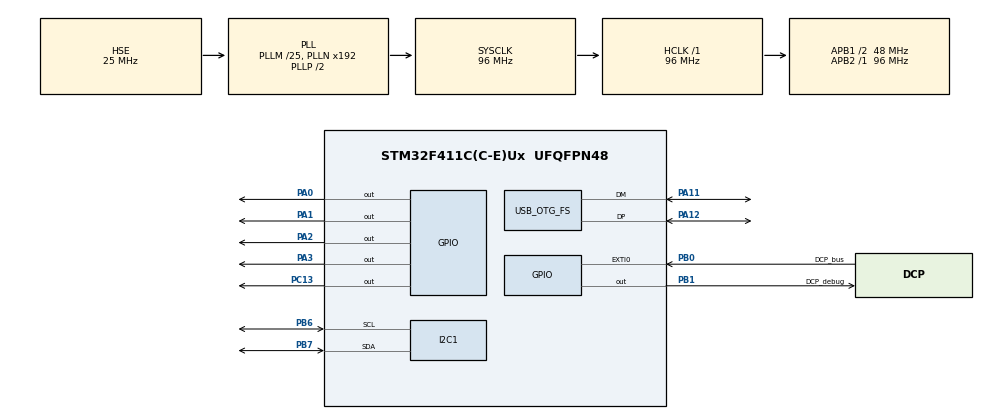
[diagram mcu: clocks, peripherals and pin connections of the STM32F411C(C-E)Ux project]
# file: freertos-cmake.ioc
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FREERTOS.Tasks01=defaultTask,0,128,StartDefaultTask,Default,NULL,Dynamic,NULL,NULL
FREERTOS.configUSE_NEWLIB_REENTRANT=1
Mcu.Family=STM32F4
Mcu.Name=STM32F411C(C-E)Ux
Mcu.Package=UFQFPN48
NVIC.EXTI0_IRQn=true\:5\:0\:false\:false\:true\:true\:true\:true\:true
NVIC.OTG_FS_IRQn=true\:5\:0\:false\:false\:true\:true\:false\:true\:true
NVIC.PriorityGroup=NVIC_PRIORITYGROUP_4
NVIC.TIM1_UP_TIM10_IRQn=true\:15\:0\:false\:false\:true\:false\:false\:true\:true
NVIC.TimeBase=TIM1_UP_TIM10_IRQn
NVIC.TimeBaseIP=TIM1
PA0-WKUP.Signal=GPIO_Output
PA1.Signal=GPIO_Output
PA11.Mode=Device_Only
PA11.Signal=USB_OTG_FS_DM
PA12.Mode=Device_Only
PA12.Signal=USB_OTG_FS_DP
PA2.Signal=GPIO_Output
PA3.Signal=GPIO_Output
PB0.GPIO_Label=DCP_bus
PB0.GPIO_ModeDefaultEXTI=GPIO_MODE_IT_FALLING
PB0.Signal=GPXTI0
PB1.GPIO_Label=DCP_debug
PB1.Signal=GPIO_Output
PB6.Mode=I2C
PB6.Signal=I2C1_SCL
PB7.Mode=I2C
PB7.Signal=I2C1_SDA
PC13-ANTI_TAMP.Signal=GPIO_Output
PC14-OSC32_IN.Mode=LSE-External-Oscillator
PC14-OSC32_IN.Signal=RCC_OSC32_IN
PC15-OSC32_OUT.Mode=LSE-External-Oscillator
PC15-OSC32_OUT.Signal=RCC_OSC32_OUT
PH0\ -\ OSC_IN.Mode=HSE-External-Oscillator
PH0\ -\ OSC_IN.Signal=RCC_OSC_IN
PH1\ -\ OSC_OUT.Mode=HSE-External-Oscillator
PH1\ -\ OSC_OUT.Signal=RCC_OSC_OUT
ProjectManager.HeapSize=0x200
ProjectManager.StackSize=0x400
ProjectManager.TargetToolchain=CMake
RCC.48MHZClocksFreq_Value=48000000
RCC.AHBFreq_Value=96000000
RCC.APB1CLKDivider=RCC_HCLK_DIV2
RCC.APB1Freq_Value=48000000
RCC.APB1TimFreq_Value=96000000
RCC.APB2Freq_Value=96000000
RCC.APB2TimFreq_Value=96000000
RCC.CortexFreq_Value=96000000
RCC.HCLKFreq_Value=96000000
RCC.HSE_VALUE=25000000
RCC.HSI_VALUE=16000000
RCC.PLLM=25
RCC.SYSCLKFreq_VALUE=96000000
RCC.SYSCLKSource=RCC_SYSCLKSOURCE_PLLCLK
RCC.VCOOutputFreq_Value=192000000
USB_DEVICE.CLASS_NAME_FS=CDC
USB_DEVICE.VirtualMode=Cdc
USB_DEVICE.VirtualModeFS=Cdc_FS
USB_OTG_FS.VirtualMode=Device_Only
VP_FREERTOS_VS_CMSIS_V1.Mode=CMSIS_V1
VP_SYS_VS_tim1.Mode=TIM1
VP_TIM2_VS_ClockSourceINT.Mode=Internal
VP_USB_DEVICE_VS_USB_DEVICE_CDC_FS.Mode=CDC_FS
board=custom

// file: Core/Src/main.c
/* USER CODE BEGIN Header */
/**
  ******************************************************************************
  * @file           : main.c
  * @brief          : Main program body
  ******************************************************************************
  * @attention
  *
  * Copyright (c) 2025 STMicroelectronics.
  * All rights reserved.
  *
  * This software is licensed under terms that can be found in the LICENSE file
  * in the root directory of this software component.
  * If no LICENSE file comes with this software, it is provided AS-IS.
  *
  ******************************************************************************
  */
/* USER CODE END Header */
#include "main.h"
#include "cmsis_os.h"
#include "usb_device.h"

/* USER CODE BEGIN Includes */

#include <string.h>

extern uint8_t CDC_Transmit_FS(uint8_t* Buf, uint16_t Len);

#include "ssd1306.h"
#include "ssd1306_fonts.h"

#include "DCP.h"
extern void BusISR(void* arg);

/* USER CODE END Includes */

/* USER CODE BEGIN PM */

#define PRINT(str) CDC_Transmit_FS((uint8_t*)str, sizeof(str))

/* USER CODE END PM */

I2C_HandleTypeDef hi2c1;

TIM_HandleTypeDef htim2;

osThreadId defaultTaskHandle;

void SystemClock_Config(void);
static void MX_GPIO_Init(void);
static void MX_TIM2_Init(void);
static void MX_I2C1_Init(void);
void StartDefaultTask(void const * argument);

/* USER CODE BEGIN 0 */

void Print7SD(unsigned int n){

    const int n1 = n%10;

    HAL_GPIO_WritePin(GPIOA, GPIO_PIN_4, GPIO_PIN_RESET);

    for (int i = 0; i < 4; ++i){
        HAL_GPIO_WritePin(GPIOA, GPIO_PIN_0 << i, (n1>>i)&0x1);
    }

    HAL_GPIO_WritePin(GPIOA, GPIO_PIN_4, GPIO_PIN_SET);

    if (n < 10) return;

    const int n2 = (n/10)%10;

    HAL_GPIO_WritePin(GPIOA, GPIO_PIN_5, GPIO_PIN_RESET);
    for (int i = 0; i < 4; ++i){
        HAL_GPIO_WritePin(GPIOA, GPIO_PIN_0 << i, (n2>>i)&0x1);
    }
    HAL_GPIO_WritePin(GPIOA, GPIO_PIN_5, GPIO_PIN_SET);
}

void HAL_GPIO_EXTI_Callback(uint16_t GPIO_Pin){

    if(GPIO_Pin == GPIO_PIN_0) {
        BusISR((void*)GPIO_Pin);
    } else {
      __NOP();
    }
}

void SanityCheck(unsigned const int size, uint8_t const msg[]){

    uint8_t str[2] = {0};

    for (unsigned i = 0; i < size; ++i)
        for (int j = 7; j >= 0; --j){
            str[0] = '0' + ((msg[i] >> j) & 0x1);
            CDC_Transmit_FS(str, 1);
        }
    PRINT("\r\n");
}

struct SensorData {float t; float h; unsigned v; unsigned a; unsigned c;};

void PrintSensorOLED(struct SensorData const * const sd){

	char data[5][20];
    unsigned f[2][2] = {
        {(int)sd->t, (sd->t-(int)sd->t)*10},
        {(int)sd->h, (sd->h-(int)sd->h)*10}};

	snprintf(data[0], 20, "temp: %i,%iC", f[0][0], f[0][1]);
	snprintf(data[1], 20, "hum: %i,%i%%", f[1][0], f[1][1]);
	snprintf(data[2], 20, "AQI: %i", sd->a);
	snprintf(data[3], 20, "tVOC: %ippb", sd->v);
	snprintf(data[4], 20, "eCO2: %ippm", sd->c);

    PRINT(data[0]);
    PRINT(data[1]);

	ssd1306_Fill(Black);
	ssd1306_SetCursor(0, 0);

	for (int i = 0; i < 5; ++i){
		ssd1306_WriteString(data[i], Font_6x8, White);
		ssd1306_SetCursor(0, 9 * (i+1));
	}

	ssd1306_UpdateScreen();
}

/* USER CODE END 0 */

int main(void)
{

  /* MCU Configuration--------------------------------------------------------*/

  /* Reset of all peripherals, Initializes the Flash interface and the Systick. */
  HAL_Init();

  /* Configure the system clock */
  SystemClock_Config();

  /* Initialize all configured peripherals */
  MX_GPIO_Init();
  MX_TIM2_Init();
  MX_I2C1_Init();
  /* USER CODE BEGIN 2 */
    ssd1306_Init();

    ssd1306_WriteString("starting", Font_6x8, White);
    ssd1306_UpdateScreen();
    ssd1306_SetCursor(0,0);

    Print7SD(0x0);
  /* USER CODE END 2 */

  /* USER CODE BEGIN RTOS_TIMERS */
  /* start timers, add new ones, ... */
    HAL_TIM_Base_Start(&htim2);
  /* USER CODE END RTOS_TIMERS */

  /* Create the thread(s) */
  /* definition and creation of defaultTask */
  osThreadDef(defaultTask, StartDefaultTask, osPriorityNormal, 0, 512);
  defaultTaskHandle = osThreadCreate(osThread(defaultTask), NULL);

  /* Start scheduler */
  osKernelStart();

  /* We should never get here as control is now taken by the scheduler */

  /* Infinite loop */
  while (1)
  {

  }
}

void SystemClock_Config(void)
{
  RCC_OscInitTypeDef RCC_OscInitStruct = {0};
  RCC_ClkInitTypeDef RCC_ClkInitStruct = {0};

  /** Configure the main internal regulator output voltage
  */
  __HAL_RCC_PWR_CLK_ENABLE();
  __HAL_PWR_VOLTAGESCALING_CONFIG(PWR_REGULATOR_VOLTAGE_SCALE1);

  /** Initializes the RCC Oscillators according to the specified parameters
  * in the RCC_OscInitTypeDef structure.
  */
  RCC_OscInitStruct.OscillatorType = RCC_OSCILLATORTYPE_HSE;
  RCC_OscInitStruct.HSEState = RCC_HSE_ON;
  RCC_OscInitStruct.PLL.PLLState = RCC_PLL_ON;
  RCC_OscInitStruct.PLL.PLLSource = RCC_PLLSOURCE_HSE;
  RCC_OscInitStruct.PLL.PLLM = 25;
  RCC_OscInitStruct.PLL.PLLN = 192;
  RCC_OscInitStruct.PLL.PLLP = RCC_PLLP_DIV2;
  RCC_OscInitStruct.PLL.PLLQ = 4;
  if (HAL_RCC_OscConfig(&RCC_OscInitStruct) != HAL_OK)
  {
    Error_Handler();
  }

  /** Initializes the CPU, AHB and APB buses clocks
  */
  RCC_ClkInitStruct.ClockType = RCC_CLOCKTYPE_HCLK|RCC_CLOCKTYPE_SYSCLK
                              |RCC_CLOCKTYPE_PCLK1|RCC_CLOCKTYPE_PCLK2;
  RCC_ClkInitStruct.SYSCLKSource = RCC_SYSCLKSOURCE_PLLCLK;
  RCC_ClkInitStruct.AHBCLKDivider = RCC_SYSCLK_DIV1;
  RCC_ClkInitStruct.APB1CLKDivider = RCC_HCLK_DIV2;
  RCC_ClkInitStruct.APB2CLKDivider = RCC_HCLK_DIV1;

  if (HAL_RCC_ClockConfig(&RCC_ClkInitStruct, FLASH_LATENCY_3) != HAL_OK)
  {
    Error_Handler();
  }
}

static void MX_I2C1_Init(void)
{

  hi2c1.Instance = I2C1;
  hi2c1.Init.ClockSpeed = 100000;
  hi2c1.Init.DutyCycle = I2C_DUTYCYCLE_2;
  hi2c1.Init.OwnAddress1 = 0;
  hi2c1.Init.AddressingMode = I2C_ADDRESSINGMODE_7BIT;
  hi2c1.Init.DualAddressMode = I2C_DUALADDRESS_DISABLE;
  hi2c1.Init.OwnAddress2 = 0;
  hi2c1.Init.GeneralCallMode = I2C_GENERALCALL_DISABLE;
  hi2c1.Init.NoStretchMode = I2C_NOSTRETCH_DISABLE;
  if (HAL_I2C_Init(&hi2c1) != HAL_OK)
  {
    Error_Handler();
  }

}

static void MX_TIM2_Init(void)
{

  TIM_ClockConfigTypeDef sClockSourceConfig = {0};
  TIM_MasterConfigTypeDef sMasterConfig = {0};

  htim2.Instance = TIM2;
  htim2.Init.Prescaler = 0;
  htim2.Init.CounterMode = TIM_COUNTERMODE_UP;
  htim2.Init.Period = 4294967295;
  htim2.Init.ClockDivision = TIM_CLOCKDIVISION_DIV1;
  htim2.Init.AutoReloadPreload = TIM_AUTORELOAD_PRELOAD_DISABLE;
  if (HAL_TIM_Base_Init(&htim2) != HAL_OK)
  {
    Error_Handler();
  }
  sClockSourceConfig.ClockSource = TIM_CLOCKSOURCE_INTERNAL;
  if (HAL_TIM_ConfigClockSource(&htim2, &sClockSourceConfig) != HAL_OK)
  {
    Error_Handler();
  }
  sMasterConfig.MasterOutputTrigger = TIM_TRGO_RESET;
  sMasterConfig.MasterSlaveMode = TIM_MASTERSLAVEMODE_DISABLE;
  if (HAL_TIMEx_MasterConfigSynchronization(&htim2, &sMasterConfig) != HAL_OK)
  {
    Error_Handler();
  }

}

static void MX_GPIO_Init(void)
{
  GPIO_InitTypeDef GPIO_InitStruct = {0};

  /* GPIO Ports Clock Enable */
  __HAL_RCC_GPIOC_CLK_ENABLE();
  __HAL_RCC_GPIOH_CLK_ENABLE();
  __HAL_RCC_GPIOA_CLK_ENABLE();
  __HAL_RCC_GPIOB_CLK_ENABLE();

  /*Configure GPIO pin Output Level */
  HAL_GPIO_WritePin(GPIOA, GPIO_PIN_0|GPIO_PIN_1|GPIO_PIN_2|GPIO_PIN_3|GPIO_PIN_4|GPIO_PIN_5, GPIO_PIN_RESET);

  /*Configure GPIO pin Output Level */
  HAL_GPIO_WritePin(DCP_debug_GPIO_Port, DCP_debug_Pin, GPIO_PIN_RESET);

  /*Configure GPIO pins : PA0 PA1 PA2 PA3 */
  GPIO_InitStruct.Pin = GPIO_PIN_0|GPIO_PIN_1|GPIO_PIN_2|GPIO_PIN_3|GPIO_PIN_4|GPIO_PIN_5;
  GPIO_InitStruct.Mode = GPIO_MODE_OUTPUT_PP;
  GPIO_InitStruct.Pull = GPIO_NOPULL;
  GPIO_InitStruct.Speed = GPIO_SPEED_FREQ_LOW;
  HAL_GPIO_Init(GPIOA, &GPIO_InitStruct);

  HAL_GPIO_WritePin(GPIOA, GPIO_PIN_4|GPIO_PIN_5, GPIO_PIN_SET);

  /*Configure GPIO pin : DCP_bus_Pin
 */
  GPIO_InitStruct.Pin = DCP_bus_Pin;
  GPIO_InitStruct.Mode = GPIO_MODE_IT_FALLING;
  GPIO_InitStruct.Pull = GPIO_PULLUP;
  HAL_GPIO_Init(DCP_bus_GPIO_Port, &GPIO_InitStruct);

  /*Configure GPIO pin : DCP_debug_Pin */
  GPIO_InitStruct.Pin = DCP_debug_Pin;
  GPIO_InitStruct.Mode = GPIO_MODE_OUTPUT_PP;
  GPIO_InitStruct.Pull = GPIO_NOPULL;
  GPIO_InitStruct.Speed = GPIO_SPEED_FREQ_LOW;
  HAL_GPIO_Init(DCP_debug_GPIO_Port, &GPIO_InitStruct);

  /* EXTI interrupt init*/
  //HAL_NVIC_SetPriority(EXTI0_IRQn, 2, 0);

}

void StartDefaultTask(void const * argument)
{
  /* init code for USB_DEVICE */
  MX_USB_DEVICE_Init();
  /* USER CODE BEGIN 5 */
    (void) argument;

    struct SensorData sensorData = {0};
    const DCP_MODE mode = {.addr = 0xFF, .flags.flags = FLAG_Instant, .isController = 0, .speed = SLOW};
    struct DCP_Message_t* message = NULL;

    if (!DCPInit(0, mode)){
        PRINT("não foi possivel iniciar o barramento\r\n");
        ssd1306_WriteString("não foi possivel iniciar o barramento", Font_6x8, White);
        ssd1306_UpdateScreen();
        while(1);
    }

    HAL_NVIC_SetPriority(EXTI0_IRQn, 6, 0);
    HAL_NVIC_EnableIRQ(EXTI0_IRQn);

    ssd1306_Fill(Black);
    ssd1306_SetCursor(0, 0);
    ssd1306_WriteString("reading", Font_6x8, White);
    ssd1306_UpdateScreen();

    while(1){
        message = ReadMessage();

        if (message) {
            //button messages
            if (message->type == 0) continue;

            memcpy(&sensorData, &message->generic.payload, sizeof sensorData);

            PrintSensorOLED(&sensorData);
            Print7SD((int)sensorData.t);

            //SanityCheck(message->type, debug.data);

            PRINT("read\r\n");
            free(message);
            message = NULL;
        }

        vTaskDelay(pdMS_TO_TICKS(500));
        PRINT("reading\r\n");
    }
  /* USER CODE END 5 */
}

void HAL_TIM_PeriodElapsedCallback(TIM_HandleTypeDef *htim)
{
  if (htim->Instance == TIM1)
  {
    HAL_IncTick();
  }
}

void Error_Handler(void)
{
  /* USER CODE BEGIN Error_Handler_Debug */
  /* User can add his own implementation to report the HAL error return state */
  __disable_irq();
    Print7SD(80);
  while (1)
  {
  }
  /* USER CODE END Error_Handler_Debug */
}

#ifdef  USE_FULL_ASSERT
#include <stdlib.h>
#include <string.h>

/**
  * @brief  Reports the name of the source file and the source line number
  *         where the assert_param error has occurred.
  * @param  file: pointer to the source file name
  * @param  line: assert_param error line source number
  * @retval None
  */
void assert_failed(uint8_t *file, uint32_t line)
{
  /* USER CODE BEGIN 6 */
    char buffer[] = "assert failed";
    char sline[32];

    ssd1306_Fill(Black);
    ssd1306_SetCursor(0, 0);
    ssd1306_WriteString(buffer, Font_6x8, White);

    ssd1306_SetCursor(0, 9);
    ssd1306_WriteString(strrchr((char*)file, '/'), Font_6x8, White);

    ssd1306_SetCursor(0, 18);
    itoa(line, sline, 10);
    ssd1306_WriteString((char*)sline, Font_6x8, White);

    ssd1306_UpdateScreen();

    while(1);
  /* User can add his own implementation to report the file name and line number,
     ex: printf("Wrong parameters value: file %s on line %d\r\n", file, line) */
  /* USER CODE END 6 */
}
#endif /* USE_FULL_ASSERT */
